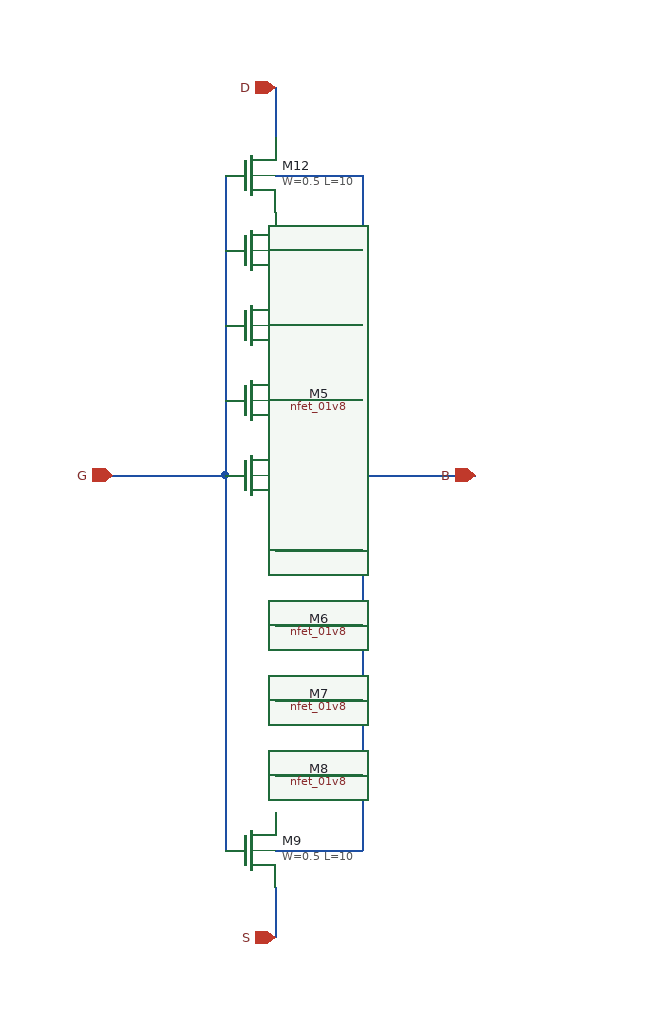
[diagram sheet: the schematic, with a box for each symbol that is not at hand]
v {xschem version=3.4.8RC file_version=1.3}
G {}
K {}
V {}
S {}
F {}
E {}
N 140 -390 230 -390 {lab=G
}
N 270 -680 270 -660 {lab=D}
N 230 -450 230 -390 {lab=G}
N 230 -510 230 -450 {lab=G}
N 230 -570 230 -510 {lab=G}
N 230 -630 230 -570 {lab=G}
N 230 -390 230 -90 {lab=G}
N 270 -700 270 -680 {lab=D}
N 270 -40 270 -20 {lab=S}
N 270 -60 270 -40 {lab=S}
N 270 -630 340 -630 {lab=G}
N 340 -630 340 -90 {lab=G}
N 270 -90 340 -90 {lab=G}
N 270 -150 340 -150 {lab=G}
N 270 -210 340 -210 {lab=G}
N 270 -270 340 -270 {lab=G}
N 270 -330 340 -330 {lab=G}
N 270 -390 340 -390 {lab=G}
N 270 -450 340 -450 {lab=G}
N 270 -510 340 -510 {lab=G}
N 270 -570 340 -570 {lab=G}
N 340 -390 430 -390 {lab=G
}
C {sky130_fd_pr/nfet_01v8.sym} 250 -630 0 0 {name=M12
W=0.5
L=10
body=GND
nf=1
mult=1
ad="expr('int((@nf + 1)/2) * @W / @nf * 0.29')"
pd="expr('2*int((@nf + 1)/2) * (@W / @nf + 0.29)')"
as="expr('int((@nf + 2)/2) * @W / @nf * 0.29')"
ps="expr('2*int((@nf + 2)/2) * (@W / @nf + 0.29)')"
nrd="expr('0.29 / @W ')" nrs="expr('0.29 / @W ')"
sa=0 sb=0 sd=0
model=nfet_01v8
spiceprefix=X
}
C {sky130_fd_pr/nfet_01v8.sym} 250 -570 0 0 {name=M1
W=0.5
L=10
body=GND
nf=1
mult=1
ad="expr('int((@nf + 1)/2) * @W / @nf * 0.29')"
pd="expr('2*int((@nf + 1)/2) * (@W / @nf + 0.29)')"
as="expr('int((@nf + 2)/2) * @W / @nf * 0.29')"
ps="expr('2*int((@nf + 2)/2) * (@W / @nf + 0.29)')"
nrd="expr('0.29 / @W ')" nrs="expr('0.29 / @W ')"
sa=0 sb=0 sd=0
model=nfet_01v8
spiceprefix=X
}
C {sky130_fd_pr/nfet_01v8.sym} 250 -510 0 0 {name=M2
W=0.5
L=10
body=GND
nf=1
mult=1
ad="expr('int((@nf + 1)/2) * @W / @nf * 0.29')"
pd="expr('2*int((@nf + 1)/2) * (@W / @nf + 0.29)')"
as="expr('int((@nf + 2)/2) * @W / @nf * 0.29')"
ps="expr('2*int((@nf + 2)/2) * (@W / @nf + 0.29)')"
nrd="expr('0.29 / @W ')" nrs="expr('0.29 / @W ')"
sa=0 sb=0 sd=0
model=nfet_01v8
spiceprefix=X
}
C {sky130_fd_pr/nfet_01v8.sym} 250 -450 0 0 {name=M3
W=0.5
L=10
body=GND
nf=1
mult=1
ad="expr('int((@nf + 1)/2) * @W / @nf * 0.29')"
pd="expr('2*int((@nf + 1)/2) * (@W / @nf + 0.29)')"
as="expr('int((@nf + 2)/2) * @W / @nf * 0.29')"
ps="expr('2*int((@nf + 2)/2) * (@W / @nf + 0.29)')"
nrd="expr('0.29 / @W ')" nrs="expr('0.29 / @W ')"
sa=0 sb=0 sd=0
model=nfet_01v8
spiceprefix=X
}
C {sky130_fd_pr/nfet_01v8.sym} 250 -390 0 0 {name=M4
W=0.5
L=10
body=GND
nf=1
mult=1
ad="expr('int((@nf + 1)/2) * @W / @nf * 0.29')"
pd="expr('2*int((@nf + 1)/2) * (@W / @nf + 0.29)')"
as="expr('int((@nf + 2)/2) * @W / @nf * 0.29')"
ps="expr('2*int((@nf + 2)/2) * (@W / @nf + 0.29)')"
nrd="expr('0.29 / @W ')" nrs="expr('0.29 / @W ')"
sa=0 sb=0 sd=0
model=nfet_01v8
spiceprefix=X
}
C {sky130_fd_pr/nfet_01v8.sym} 250 -330 0 0 {name=M5
W=0.5
L=10
body=GND
nf=1
mult=1
ad="expr('int((@nf + 1)/2) * @W / @nf * 0.29')"
pd="expr('2*int((@nf + 1)/2) * (@W / @nf + 0.29)')"
as="expr('int((@nf + 2)/2) * @W / @nf * 0.29')"
ps="expr('2*int((@nf + 2)/2) * (@W / @nf + 0.29)')"
nrd="expr('0.29 / @W ')" nrs="expr('0.29 / @W ')"
sa=0 sb=0 sd=0
model=nfet_01v8
spiceprefix=X
}
C {sky130_fd_pr/nfet_01v8.sym} 250 -270 0 0 {name=M6
W=0.5
L=10
body=GND
nf=1
mult=1
ad="expr('int((@nf + 1)/2) * @W / @nf * 0.29')"
pd="expr('2*int((@nf + 1)/2) * (@W / @nf + 0.29)')"
as="expr('int((@nf + 2)/2) * @W / @nf * 0.29')"
ps="expr('2*int((@nf + 2)/2) * (@W / @nf + 0.29)')"
nrd="expr('0.29 / @W ')" nrs="expr('0.29 / @W ')"
sa=0 sb=0 sd=0
model=nfet_01v8
spiceprefix=X
}
C {sky130_fd_pr/nfet_01v8.sym} 250 -210 0 0 {name=M7
W=0.5
L=10
body=GND
nf=1
mult=1
ad="expr('int((@nf + 1)/2) * @W / @nf * 0.29')"
pd="expr('2*int((@nf + 1)/2) * (@W / @nf + 0.29)')"
as="expr('int((@nf + 2)/2) * @W / @nf * 0.29')"
ps="expr('2*int((@nf + 2)/2) * (@W / @nf + 0.29)')"
nrd="expr('0.29 / @W ')" nrs="expr('0.29 / @W ')"
sa=0 sb=0 sd=0
model=nfet_01v8
spiceprefix=X
}
C {sky130_fd_pr/nfet_01v8.sym} 250 -150 0 0 {name=M8
W=0.5
L=10
body=GND
nf=1
mult=1
ad="expr('int((@nf + 1)/2) * @W / @nf * 0.29')"
pd="expr('2*int((@nf + 1)/2) * (@W / @nf + 0.29)')"
as="expr('int((@nf + 2)/2) * @W / @nf * 0.29')"
ps="expr('2*int((@nf + 2)/2) * (@W / @nf + 0.29)')"
nrd="expr('0.29 / @W ')" nrs="expr('0.29 / @W ')"
sa=0 sb=0 sd=0
model=nfet_01v8
spiceprefix=X
}
C {sky130_fd_pr/nfet_01v8.sym} 250 -90 0 0 {name=M9
W=0.5
L=10
body=GND
nf=1
mult=1
ad="expr('int((@nf + 1)/2) * @W / @nf * 0.29')"
pd="expr('2*int((@nf + 1)/2) * (@W / @nf + 0.29)')"
as="expr('int((@nf + 2)/2) * @W / @nf * 0.29')"
ps="expr('2*int((@nf + 2)/2) * (@W / @nf + 0.29)')"
nrd="expr('0.29 / @W ')" nrs="expr('0.29 / @W ')"
sa=0 sb=0 sd=0
model=nfet_01v8
spiceprefix=X
}
C {iopin.sym} 270 -700 0 0 {name=p1 lab=D}
C {iopin.sym} 140 -390 2 0 {name=p2 lab=G}
C {iopin.sym} 270 -20 2 0 {name=p3 lab=S}
C {iopin.sym} 430 -390 0 0 {name=p4 lab=B}
